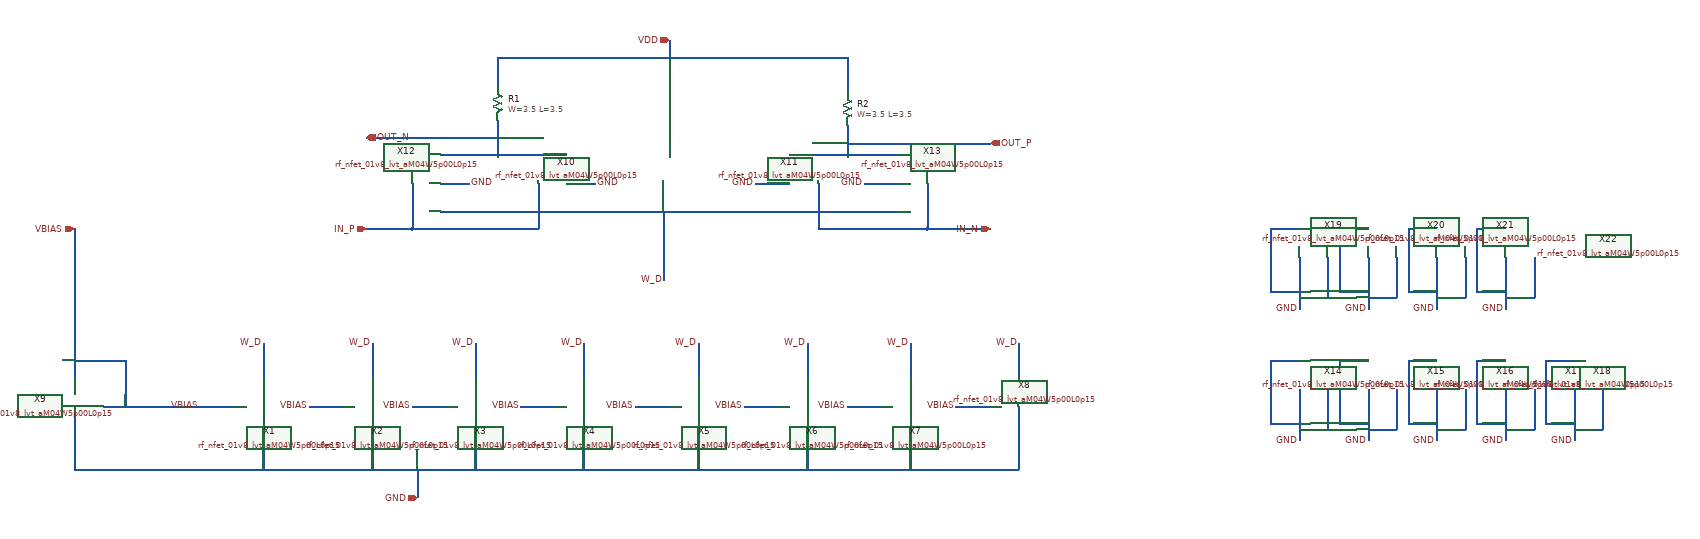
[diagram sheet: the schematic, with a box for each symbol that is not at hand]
v {xschem version=3.0.0 file_version=1.2 }
G {}
K {}
V {}
S {}
E {}
N 220 -110 220 0 {
lab=GND}
N 220 -220 220 -160 {
lab=W_D}
N 110 -110 170 -110 {
lab=VBIAS}
N 410 -110 410 0 {
lab=GND}
N 410 -220 410 -160 {
lab=W_D}
N 300 -110 360 -110 {
lab=VBIAS}
N 590 -110 590 0 {
lab=GND}
N 590 -220 590 -160 {
lab=W_D}
N 480 -110 540 -110 {
lab=VBIAS}
N 780 -110 780 0 {
lab=GND}
N 780 -220 780 -160 {
lab=W_D}
N 670 -110 730 -110 {
lab=VBIAS}
N 980 -110 980 0 {
lab=GND}
N 980 -220 980 -160 {
lab=W_D}
N 870 -110 930 -110 {
lab=VBIAS}
N 1170 -110 1170 0 {
lab=GND}
N 1170 -220 1170 -160 {
lab=W_D}
N 1060 -110 1120 -110 {
lab=VBIAS}
N 1350 -110 1350 0 {
lab=GND}
N 1350 -220 1350 -160 {
lab=W_D}
N 1240 -110 1300 -110 {
lab=VBIAS}
N 1540 -110 1540 0 {
lab=GND}
N 1540 -220 1540 -160 {
lab=W_D}
N 1430 -110 1490 -110 {
lab=VBIAS}
N -60 -110 110 -110 {
lab=VBIAS}
N -110 -110 -110 0 {
lab=GND}
N -110 -230 -110 -160 {
lab=VBIAS}
N -110 -190 -20 -190 {
lab=VBIAS}
N -20 -190 -20 -110 {
lab=VBIAS}
N 750 -500 800 -500 {
lab=GND}
N 1080 -500 1140 -500 {
lab=GND}
N 530 -500 580 -500 {
lab=GND}
N 1270 -500 1330 -500 {
lab=GND}
N 530 -450 1330 -450 {
lab=W_D}
N 530 -550 750 -550 {
lab=OUT_N}
N 1140 -550 1330 -550 {
lab=OUT_P}
N 700 -500 700 -420 {
lab=IN_P}
N 480 -500 480 -420 {
lab=IN_P}
N 480 -420 700 -420 {
lab=IN_P}
N 1190 -500 1190 -420 {
lab=IN_N}
N 1380 -500 1380 -420 {
lab=IN_N}
N 1190 -420 1380 -420 {
lab=IN_N}
N -110 0 1540 0 {
lab=GND}
N 630 -610 630 -550 {
lab=OUT_N}
N 1240 -600 1240 -550 {
lab=OUT_P}
N 630 -720 630 -670 {
lab=VDD}
N 630 -720 1240 -720 {
lab=VDD}
N 1240 -720 1240 -660 {
lab=VDD}
N 930 -750 930 -720 {
lab=VDD}
N 490 0 490 50 {
lab=GND}
N 1380 -420 1490 -420 {
lab=IN_N}
N 400 -420 480 -420 {
lab=IN_P}
N 1240 -570 1430 -570 {
lab=OUT_P}
N 400 -580 630 -580 {
lab=OUT_N}
N 1430 -570 1490 -570 {
lab=OUT_P}
N -110 -320 -110 -290 {
lab=VBIAS}
N 920 -450 920 -420 {
lab=W_D}
N 920 -360 920 -330 {
lab=W_D}
N -110 -290 -110 -230 {
lab=VBIAS}
N -110 -420 -110 -390 {
lab=VBIAS}
N -110 -330 -110 -320 {
lab=VBIAS}
N -110 -390 -110 -330 {
lab=VBIAS}
N 920 -420 920 -360 {
lab=W_D}
N 2030 -140 2030 -90 {}
N 2080 -140 2080 -90 {}
N 1980 -190 2030 -190 {}
N 1980 -190 1980 -90 {}
N 2030 -90 2030 -60 {}
N 1980 -90 1980 -80 {}
N 1980 -80 2030 -80 {}
N 2080 -90 2080 -70 {}
N 2030 -70 2080 -70 {}
N 2030 -60 2030 -50 {}
N 2150 -140 2150 -90 {}
N 2200 -140 2200 -90 {}
N 2100 -190 2150 -190 {}
N 2100 -190 2100 -90 {}
N 2150 -90 2150 -60 {}
N 2100 -90 2100 -80 {}
N 2100 -80 2150 -80 {}
N 2200 -90 2200 -70 {}
N 2150 -70 2200 -70 {}
N 2150 -60 2150 -50 {}
N 2270 -140 2270 -90 {}
N 2320 -140 2320 -90 {}
N 2220 -190 2270 -190 {}
N 2220 -190 2220 -90 {}
N 2270 -90 2270 -60 {}
N 2220 -90 2220 -80 {}
N 2220 -80 2270 -80 {}
N 2320 -90 2320 -70 {}
N 2270 -70 2320 -70 {}
N 2270 -60 2270 -50 {}
N 2390 -140 2390 -90 {}
N 2440 -140 2440 -90 {}
N 2340 -190 2390 -190 {}
N 2340 -190 2340 -90 {}
N 2390 -90 2390 -60 {}
N 2340 -90 2340 -80 {}
N 2340 -80 2390 -80 {}
N 2440 -90 2440 -70 {}
N 2390 -70 2440 -70 {}
N 2390 -60 2390 -50 {}
N 2510 -140 2510 -90 {}
N 2560 -140 2560 -90 {}
N 2460 -190 2510 -190 {}
N 2460 -190 2460 -90 {}
N 2510 -90 2510 -60 {}
N 2460 -90 2460 -80 {}
N 2460 -80 2510 -80 {}
N 2560 -90 2560 -70 {}
N 2510 -70 2560 -70 {}
N 2510 -60 2510 -50 {}
N 2030 -370 2030 -320 {}
N 2080 -370 2080 -320 {}
N 1980 -420 2030 -420 {}
N 1980 -420 1980 -320 {}
N 2030 -320 2030 -290 {}
N 1980 -320 1980 -310 {}
N 1980 -310 2030 -310 {}
N 2080 -320 2080 -300 {}
N 2030 -300 2080 -300 {}
N 2030 -290 2030 -280 {}
N 2150 -370 2150 -320 {}
N 2200 -370 2200 -320 {}
N 2100 -420 2150 -420 {}
N 2100 -420 2100 -320 {}
N 2150 -320 2150 -290 {}
N 2100 -320 2100 -310 {}
N 2100 -310 2150 -310 {}
N 2200 -320 2200 -300 {}
N 2150 -300 2200 -300 {}
N 2150 -290 2150 -280 {}
N 2270 -370 2270 -320 {}
N 2320 -370 2320 -320 {}
N 2220 -420 2270 -420 {}
N 2220 -420 2220 -320 {}
N 2270 -320 2270 -290 {}
N 2220 -320 2220 -310 {}
N 2220 -310 2270 -310 {}
N 2320 -320 2320 -300 {}
N 2270 -300 2320 -300 {}
N 2270 -290 2270 -280 {}
N 2390 -370 2390 -320 {}
N 2440 -370 2440 -320 {}
N 2340 -420 2390 -420 {}
N 2340 -420 2340 -320 {}
N 2390 -320 2390 -290 {}
N 2340 -320 2340 -310 {}
N 2340 -310 2390 -310 {}
N 2440 -320 2440 -300 {}
N 2390 -300 2440 -300 {}
N 2390 -290 2390 -280 {}
C {devices/lab_pin.sym} 110 -110 0 0 {name=l1 sig_type=std_logic lab=VBIAS}
C {devices/lab_pin.sym} 220 -220 0 0 {name=l2 sig_type=std_logic lab=W_D}
C {devices/lab_pin.sym} 300 -110 0 0 {name=l4 sig_type=std_logic lab=VBIAS}
C {devices/lab_pin.sym} 410 -220 0 0 {name=l5 sig_type=std_logic lab=W_D}
C {devices/lab_pin.sym} 480 -110 0 0 {name=l7 sig_type=std_logic lab=VBIAS}
C {devices/lab_pin.sym} 590 -220 0 0 {name=l8 sig_type=std_logic lab=W_D}
C {devices/lab_pin.sym} 670 -110 0 0 {name=l10 sig_type=std_logic lab=VBIAS}
C {devices/lab_pin.sym} 780 -220 0 0 {name=l11 sig_type=std_logic lab=W_D}
C {devices/lab_pin.sym} 870 -110 0 0 {name=l13 sig_type=std_logic lab=VBIAS}
C {devices/lab_pin.sym} 980 -220 0 0 {name=l14 sig_type=std_logic lab=W_D}
C {devices/lab_pin.sym} 1060 -110 0 0 {name=l16 sig_type=std_logic lab=VBIAS}
C {devices/lab_pin.sym} 1170 -220 0 0 {name=l17 sig_type=std_logic lab=W_D}
C {devices/lab_pin.sym} 1240 -110 0 0 {name=l19 sig_type=std_logic lab=VBIAS}
C {devices/lab_pin.sym} 1350 -220 0 0 {name=l20 sig_type=std_logic lab=W_D}
C {devices/lab_pin.sym} 1430 -110 0 0 {name=l22 sig_type=std_logic lab=VBIAS}
C {devices/lab_pin.sym} 1540 -220 0 0 {name=l23 sig_type=std_logic lab=W_D}
C {devices/iopin.sym} -110 -420 3 0 {name=p1 lab=VBIAS}
C {rf_nfet_01v8_lvt_aM04W5p00L0p15.sym} 680 -430 0 0 {name=X10}
C {rf_nfet_01v8_lvt_aM04W5p00L0p15.sym} 1210 -430 0 1 {name=X11}
C {devices/lab_pin.sym} 1080 -500 0 0 {name=l26 sig_type=std_logic lab=GND}
C {devices/lab_pin.sym} 800 -500 2 0 {name=l27 sig_type=std_logic lab=GND}
C {rf_nfet_01v8_lvt_aM04W5p00L0p15.sym} 460 -430 0 0 {name=X12}
C {devices/lab_pin.sym} 580 -500 2 0 {name=l28 sig_type=std_logic lab=GND}
C {rf_nfet_01v8_lvt_aM04W5p00L0p15.sym} 1400 -430 0 1 {name=X13}
C {devices/lab_pin.sym} 1270 -500 0 0 {name=l29 sig_type=std_logic lab=GND}
C {devices/lab_pin.sym} 920 -330 3 0 {name=l30 sig_type=std_logic lab=W_D}
C {devices/iopin.sym} 930 -750 3 0 {name=p2 lab=VDD}
C {devices/iopin.sym} 490 50 1 0 {name=p3 lab=GND}
C {devices/opin.sym} 1490 -570 0 0 {name=p4 lab=OUT_P}
C {devices/opin.sym} 400 -580 2 0 {name=p5 lab=OUT_N}
C {devices/ipin.sym} 400 -420 0 0 {name=p6 lab=IN_P}
C {devices/ipin.sym} 1490 -420 2 0 {name=p7 lab=IN_N}
C {sky130_fd_pr/res_generic_po.sym} 630 -640 0 0 {name=R1
W=3.5
L=3.5
model=res_generic_po
mult=1}
C {sky130_fd_pr/res_generic_po.sym} 1240 -630 0 0 {name=R2
W=3.5
L=3.5
model=res_generic_po
mult=1}
C {rf_nfet_01v8_lvt_aM04W5p00L0p15.sym} -40 -40 0 1 {name=X9}
C {rf_nfet_01v8_lvt_aM04W5p00L0p15.sym} 150 -40 0 0 {name=X1}
C {rf_nfet_01v8_lvt_aM04W5p00L0p15.sym} 340 -40 0 0 {name=X2}
C {rf_nfet_01v8_lvt_aM04W5p00L0p15.sym} 520 -40 0 0 {name=X3}
C {rf_nfet_01v8_lvt_aM04W5p00L0p15.sym} 710 -40 0 0 {name=X4}
C {rf_nfet_01v8_lvt_aM04W5p00L0p15.sym} 910 -40 0 0 {name=X5}
C {rf_nfet_01v8_lvt_aM04W5p00L0p15.sym} 1100 -40 0 0 {name=X6}
C {rf_nfet_01v8_lvt_aM04W5p00L0p15.sym} 1280 -40 0 0 {name=X7}
C {rf_nfet_01v8_lvt_aM04W5p00L0p15.sym} 1470 -40 0 0 {name=X8}
C {rf_nfet_01v8_lvt_aM04W5p00L0p15.sym} 2100 -70 0 1 {name=X14}
C {devices/lab_pin.sym} 2030 -50 3 0 {name=l3 sig_type=std_logic lab=GND}
C {rf_nfet_01v8_lvt_aM04W5p00L0p15.sym} 2220 -70 0 1 {name=X15}
C {devices/lab_pin.sym} 2150 -50 3 0 {name=l6 sig_type=std_logic lab=GND}
C {rf_nfet_01v8_lvt_aM04W5p00L0p15.sym} 2340 -70 0 1 {name=X16}
C {devices/lab_pin.sym} 2270 -50 3 0 {name=l9 sig_type=std_logic lab=GND}
C {rf_nfet_01v8_lvt_aM04W5p00L0p15.sym} 2460 -70 0 1 {name=X17}
C {devices/lab_pin.sym} 2390 -50 3 0 {name=l12 sig_type=std_logic lab=GND}
C {rf_nfet_01v8_lvt_aM04W5p00L0p15.sym} 2580 -70 0 1 {name=X18}
C {devices/lab_pin.sym} 2510 -50 3 0 {name=l15 sig_type=std_logic lab=GND}
C {rf_nfet_01v8_lvt_aM04W5p00L0p15.sym} 2100 -300 0 1 {name=X19}
C {devices/lab_pin.sym} 2030 -280 3 0 {name=l18 sig_type=std_logic lab=GND}
C {rf_nfet_01v8_lvt_aM04W5p00L0p15.sym} 2220 -300 0 1 {name=X20}
C {devices/lab_pin.sym} 2150 -280 3 0 {name=l21 sig_type=std_logic lab=GND}
C {rf_nfet_01v8_lvt_aM04W5p00L0p15.sym} 2340 -300 0 1 {name=X21}
C {devices/lab_pin.sym} 2270 -280 3 0 {name=l24 sig_type=std_logic lab=GND}
C {rf_nfet_01v8_lvt_aM04W5p00L0p15.sym} 2460 -300 0 1 {name=X22}
C {devices/lab_pin.sym} 2390 -280 3 0 {name=l25 sig_type=std_logic lab=GND}
